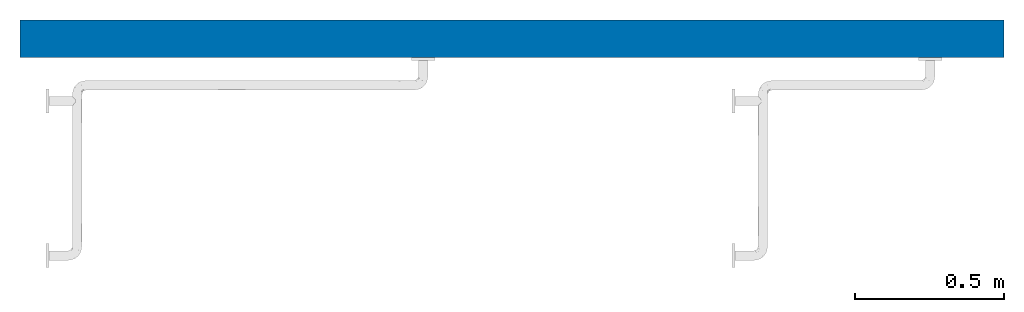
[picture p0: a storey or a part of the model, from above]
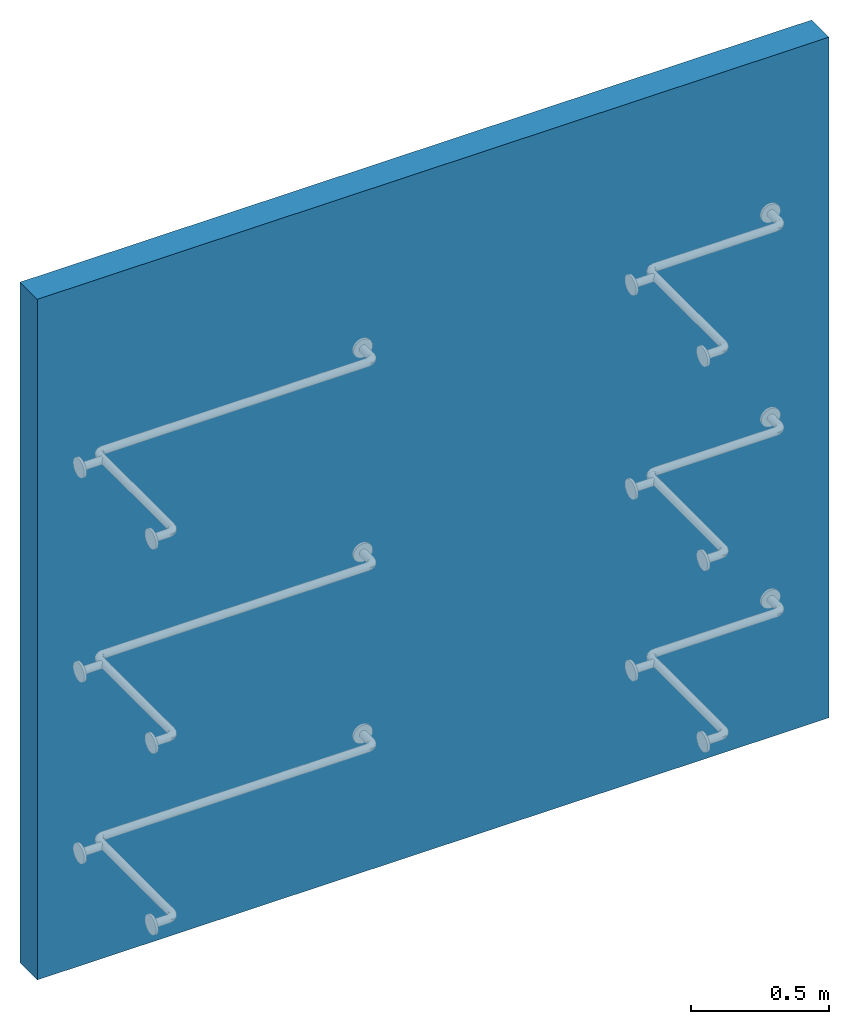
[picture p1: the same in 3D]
Properties of the parts of a building model (IFC2X3)

# File
Description: ViewDefinition [CoordinationView_V2.0]
File name: Project Number
Time: 2020-03-13T16:21:01
Written by: The EXPRESS Data Manager Version 5.02.0100.07 : 28 Aug 2013
Made in: 20190507_1515(x64) - Exporter 17.0.517.0 - Alternate UI 17.15.0.0
Comment: STEP Physical File produced by: The EXPRESS Data Manager Version 5.02.0100.07 : 28 Aug 2013 * Module: EDMstepFileFactory/EDMstandAlone * Creation date: Fri Mar 13 16:21:01 2020 * Host: DESKTOP-KN3O7NT * Database: C:\Users\SARAHS~1\AppData\Local\Temp\{BC8E3BB7-5FA7-4608-B102-5EC64DD7A695}\ifc * Database version: 5507 * Database creation date: Fri Mar 13 16:20:55 2020 * Schema: IFC2X3 * Model: DataRepository.ifc * Model creation date: Fri Mar 13 16:20:56 2020 * Header model: DataRepository.ifc_HeaderModel * Header model creation date: Fri Mar 13 16:20:56 2020 * EDMuser: sdai-user * EDMgroup: sdai-group * License ID and type: 5605 : Permanent license. Expiry date: * EDMstepFileFactory options: 020000

# IfcProject, Project Number
LongName: Project Name; Phase: Project Status

# IfcSite, Default
RefLatitude: 51, 30, 23, 112487; RefLongitude: 0, -7, -37, -956022; RefElevation: 0 mm

# IfcBuilding
Pset_BuildingCommon - NumberOfStoreys: 1

# IfcBuildingStorey, Level 0
LongName: Level 0; Elevation: 0 mm

# IfcBuildingElementProxy: Brushed Steel, Large, Duten_SStHandrls_B630:Brushed Steel, Large:273454
In: Level 0
Type - PredefinedType: USERDEFINED; Classification: E2020200 Furniture & Accessories (Uniformat); Material: Duten_Metal_BrushedStainlessSteel
Pset_BuildingElementProxyCommon - Reference: n/a
Pset_ManufacturerTypeInformation - ModelReference: Shower handrail 1300mmx700mm, Brushed Steel; Manufacturer: Duten

# IfcBuildingElementProxy: Brushed Steel, Small, Duten_SStHandrls_B630:Brushed Steel, Small:273495
In: Level 0
Type - PredefinedType: USERDEFINED; Classification: E2020200 Furniture & Accessories (Uniformat); Material: Duten_Metal_BrushedStainlessSteel
Pset_BuildingElementProxyCommon - Reference: n/a
Pset_ManufacturerTypeInformation - ModelReference: Shower handrail 700mmx700mm, Brushed Steel; Manufacturer: Duten

# IfcBuildingElementProxy: Polished Steel, Large, Duten_SStHandrls_B630:Polished Steel, Large:280565
In: Level 0
Type - PredefinedType: USERDEFINED; Classification: E2020200 Furniture & Accessories (Uniformat); Material: Duten_Metal_PolishedStainlessSteel
Pset_BuildingElementProxyCommon - Reference: n/a
Pset_ManufacturerTypeInformation - ModelReference: Shower handrail 1300mmx700mm, Polished Steel; Manufacturer: Duten

# IfcBuildingElementProxy: Polished Steel, Small, Duten_SStHandrls_B630:Polished Steel, Small:280566
In: Level 0
Type - PredefinedType: USERDEFINED; Classification: E2020200 Furniture & Accessories (Uniformat); Material: Duten_Metal_PolishedStainlessSteel
Pset_BuildingElementProxyCommon - Reference: n/a
Pset_ManufacturerTypeInformation - ModelReference: Shower handrail 700mmx700mm, Polished Steel; Manufacturer: Duten

# IfcBuildingElementProxy: White Steel, Large, Duten_SStHandrls_B630:White Steel, Large:280640
In: Level 0
Type - PredefinedType: USERDEFINED; Classification: E2020200 Furniture & Accessories (Uniformat); Material: Duten_Metal_White
Pset_BuildingElementProxyCommon - Reference: n/a
Pset_ManufacturerTypeInformation - ModelReference: Shower handrail 1300mmx700mm, White Steel; Manufacturer: Duten

# IfcBuildingElementProxy: White Steel, Small, Duten_SStHandrls_B630:White Steel, Small:280641
In: Level 0
Type - PredefinedType: USERDEFINED; Classification: E2020200 Furniture & Accessories (Uniformat); Material: Duten_Metal_White
Pset_BuildingElementProxyCommon - Reference: n/a
Pset_ManufacturerTypeInformation - ModelReference: Shower handrail 700mmx700mm, White Steel; Manufacturer: Duten

# IfcWallStandardCase: Basic Wall:Wall-Int_12P-100Blk-12P, Basic Wall:Wall-Int_12P-100Blk-12P:272549
In: Level 0
Type - PredefinedType: STANDARD; Material: Plaster 12.5 mm, Concrete Masonry Units 100 mm, Plaster 12.5 mm
Pset_WallCommon - Reference: Wall-Int_12P-100Blk-12P; LoadBearing: no; ExtendToStructure: no; IsExternal: no; ThermalTransmittance: 7.94012 kg/K/s3
